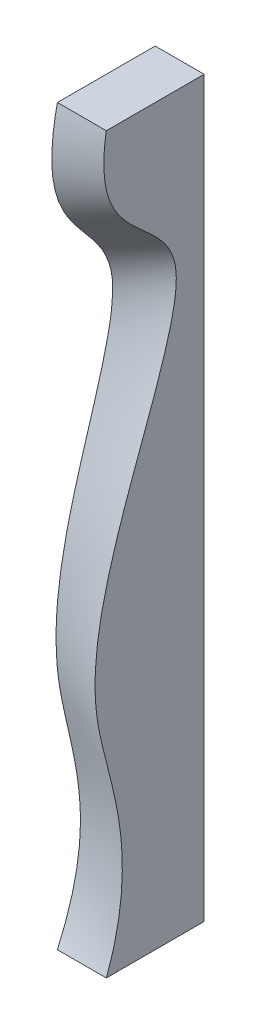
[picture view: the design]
ISO-10303-21;
HEADER;
FILE_DESCRIPTION(('STEP AP214'),'2;1');
FILE_NAME('part.step','',(''),(''),'','','');
FILE_SCHEMA(('AUTOMOTIVE_DESIGN { 1 0 10303 214 1 1 1 1 }'));
ENDSEC;
DATA;
#1=APPLICATION_CONTEXT('core data for automotive mechanical design processes');
#2=APPLICATION_PROTOCOL_DEFINITION('international standard','automotive_design',2000,#1);
#3=PRODUCT_CONTEXT('',#1,'mechanical');
#4=PRODUCT('Part','Part','',(#3));
#5=PRODUCT_RELATED_PRODUCT_CATEGORY('part','',(#4));
#6=PRODUCT_DEFINITION_FORMATION('','',#4);
#7=PRODUCT_DEFINITION_CONTEXT('part definition',#1,'design');
#8=PRODUCT_DEFINITION('design','',#6,#7);
#9=PRODUCT_DEFINITION_SHAPE('','',#8);
#10=(LENGTH_UNIT() NAMED_UNIT(*) SI_UNIT(.MILLI.,.METRE.));
#11=(NAMED_UNIT(*) PLANE_ANGLE_UNIT() SI_UNIT($,.RADIAN.));
#12=(NAMED_UNIT(*) SI_UNIT($,.STERADIAN.) SOLID_ANGLE_UNIT());
#13=UNCERTAINTY_MEASURE_WITH_UNIT(LENGTH_MEASURE(1.E-05),#10,'distance_accuracy_value','');
#14=(GEOMETRIC_REPRESENTATION_CONTEXT(3) GLOBAL_UNCERTAINTY_ASSIGNED_CONTEXT((#13)) GLOBAL_UNIT_ASSIGNED_CONTEXT((#10,
#11,#12)) REPRESENTATION_CONTEXT('',''));
#15=CARTESIAN_POINT('',(0.,0.,0.));
#16=DIRECTION('',(0.,0.,1.));
#17=DIRECTION('',(1.,0.,0.));
#18=AXIS2_PLACEMENT_3D('',#15,#16,#17);
#19=CARTESIAN_POINT('',(-350.,375.,253.120113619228));
#20=DIRECTION('',(1.,0.,0.));
#21=DIRECTION('',(0.,0.,-1.));
#22=AXIS2_PLACEMENT_3D('',#19,#20,#21);
#23=PLANE('',#22);
#24=CARTESIAN_POINT('',(-350.,375.,100.));
#25=CARTESIAN_POINT('',(-350.,373.56789695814,100.239089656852));
#26=CARTESIAN_POINT('',(-350.,372.133426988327,100.464333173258));
#27=CARTESIAN_POINT('',(-350.,369.251623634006,100.885895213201));
#28=CARTESIAN_POINT('',(-350.,367.804264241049,101.082035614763));
#29=CARTESIAN_POINT('',(-350.,364.899242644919,101.442049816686));
#30=CARTESIAN_POINT('',(-350.,363.441562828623,101.605782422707));
#31=CARTESIAN_POINT('',(-350.,360.518482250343,101.897471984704));
#32=CARTESIAN_POINT('',(-350.,359.053071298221,102.025327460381));
#33=CARTESIAN_POINT('',(-350.,356.117091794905,102.241663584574));
#34=CARTESIAN_POINT('',(-350.,354.646518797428,102.330084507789));
#35=CARTESIAN_POINT('',(-350.,351.702774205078,102.463840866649));
#36=CARTESIAN_POINT('',(-350.,350.229601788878,102.509158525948));
#37=CARTESIAN_POINT('',(-350.,347.250122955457,102.553387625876));
#38=CARTESIAN_POINT('',(-350.,345.743800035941,102.55125706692));
#39=CARTESIAN_POINT('',(-350.,342.733740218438,102.493788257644));
#40=CARTESIAN_POINT('',(-350.,341.230002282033,102.438507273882));
#41=CARTESIAN_POINT('',(-350.,338.227820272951,102.270466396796));
#42=CARTESIAN_POINT('',(-350.,336.729371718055,102.157788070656));
#43=CARTESIAN_POINT('',(-350.,333.740481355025,101.870625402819));
#44=CARTESIAN_POINT('',(-350.,332.250031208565,101.696228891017));
#45=CARTESIAN_POINT('',(-350.,329.279876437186,101.281307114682));
#46=CARTESIAN_POINT('',(-350.,327.800162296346,101.04085040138));
#47=CARTESIAN_POINT('',(-350.,324.854131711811,100.48952647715));
#48=CARTESIAN_POINT('',(-350.,323.387812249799,100.178675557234));
#49=CARTESIAN_POINT('',(-350.,320.958980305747,99.5989195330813));
#50=CARTESIAN_POINT('',(-350.,319.991518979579,99.3505932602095));
#51=CARTESIAN_POINT('',(-350.,318.065547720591,98.8200536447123));
#52=CARTESIAN_POINT('',(-350.,317.107040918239,98.5378288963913));
#53=CARTESIAN_POINT('',(-350.,315.200747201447,97.9388584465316));
#54=CARTESIAN_POINT('',(-350.,314.252961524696,97.6221088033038));
#55=CARTESIAN_POINT('',(-350.,312.369764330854,96.9537079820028));
#56=CARTESIAN_POINT('',(-350.,311.4343528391,96.6020567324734));
#57=CARTESIAN_POINT('',(-350.,309.577470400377,95.8637615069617));
#58=CARTESIAN_POINT('',(-350.,308.655999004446,95.477118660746));
#59=CARTESIAN_POINT('',(-350.,306.841363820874,94.674780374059));
#60=CARTESIAN_POINT('',(-350.,305.947983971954,94.2595735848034));
#61=CARTESIAN_POINT('',(-350.,304.177397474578,93.395896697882));
#62=CARTESIAN_POINT('',(-350.,303.300191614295,92.947424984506));
#63=CARTESIAN_POINT('',(-350.,301.56310999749,92.0181262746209));
#64=CARTESIAN_POINT('',(-350.,300.703234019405,91.5372996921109));
#65=CARTESIAN_POINT('',(-350.,299.001774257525,90.5445478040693));
#66=CARTESIAN_POINT('',(-350.,298.160188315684,90.0326261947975));
#67=CARTESIAN_POINT('',(-350.,296.496071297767,88.9792927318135));
#68=CARTESIAN_POINT('',(-350.,295.673534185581,88.4378904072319));
#69=CARTESIAN_POINT('',(-350.,294.082580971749,87.3511275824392));
#70=CARTESIAN_POINT('',(-350.,293.313360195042,86.8069433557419));
#71=CARTESIAN_POINT('',(-350.,291.792327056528,85.6946976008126));
#72=CARTESIAN_POINT('',(-350.,291.040515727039,85.1266346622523));
#73=CARTESIAN_POINT('',(-350.,289.553643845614,83.9681610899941));
#74=CARTESIAN_POINT('',(-350.,288.818593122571,83.3777378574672));
#75=CARTESIAN_POINT('',(-350.,287.365099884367,82.1767417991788));
#76=CARTESIAN_POINT('',(-350.,286.646658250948,81.5661679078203));
#77=CARTESIAN_POINT('',(-350.,285.224965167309,80.3263025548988));
#78=CARTESIAN_POINT('',(-350.,284.521728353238,79.6969943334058));
#79=CARTESIAN_POINT('',(-350.,283.130064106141,78.4221887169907));
#80=CARTESIAN_POINT('',(-350.,282.441637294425,77.7766906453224));
#81=CARTESIAN_POINT('',(-350.,280.396837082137,75.8190046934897));
#82=CARTESIAN_POINT('',(-350.,279.060828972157,74.4855238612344));
#83=CARTESIAN_POINT('',(-350.,276.411292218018,71.7573052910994));
#84=CARTESIAN_POINT('',(-350.,275.098410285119,70.361945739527));
#85=CARTESIAN_POINT('',(-350.,272.502083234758,67.5464175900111));
#86=CARTESIAN_POINT('',(-350.,271.218614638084,66.1262704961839));
#87=CARTESIAN_POINT('',(-350.,268.663277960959,63.276236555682));
#88=CARTESIAN_POINT('',(-350.,267.391407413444,61.8463518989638));
#89=CARTESIAN_POINT('',(-350.,264.840495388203,58.9926347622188));
#90=CARTESIAN_POINT('',(-350.,263.561453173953,57.5688029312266));
#91=CARTESIAN_POINT('',(-350.,261.510011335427,55.327254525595));
#92=CARTESIAN_POINT('',(-350.,260.746191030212,54.5017191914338));
#93=CARTESIAN_POINT('',(-350.,259.205543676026,52.8628311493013));
#94=CARTESIAN_POINT('',(-350.,258.428716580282,52.0494784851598));
#95=CARTESIAN_POINT('',(-350.,256.857987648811,50.4390140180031));
#96=CARTESIAN_POINT('',(-350.,256.064081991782,49.6419059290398));
#97=CARTESIAN_POINT('',(-350.,254.455574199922,48.0687110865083));
#98=CARTESIAN_POINT('',(-350.,253.64097123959,47.292625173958));
#99=CARTESIAN_POINT('',(-350.,251.993996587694,45.7724161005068));
#100=CARTESIAN_POINT('',(-350.,251.161810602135,45.0280924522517));
#101=CARTESIAN_POINT('',(-350.,249.470785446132,43.5704691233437));
#102=CARTESIAN_POINT('',(-350.,248.611949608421,42.8571655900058));
#103=CARTESIAN_POINT('',(-350.,246.865450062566,41.4672465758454));
#104=CARTESIAN_POINT('',(-350.,245.977795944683,40.790619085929));
#105=CARTESIAN_POINT('',(-350.,244.171990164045,39.4795445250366));
#106=CARTESIAN_POINT('',(-350.,243.253843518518,38.8450905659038));
#107=CARTESIAN_POINT('',(-350.,241.383239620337,37.6217034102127));
#108=CARTESIAN_POINT('',(-350.,240.430678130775,37.0329291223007));
#109=CARTESIAN_POINT('',(-350.,238.494672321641,35.9083356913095));
#110=CARTESIAN_POINT('',(-350.,237.511226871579,35.3725184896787));
#111=CARTESIAN_POINT('',(-350.,235.515305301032,34.3582211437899));
#112=CARTESIAN_POINT('',(-350.,234.502832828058,33.8797338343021));
#113=CARTESIAN_POINT('',(-350.,232.451607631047,32.9832570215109));
#114=CARTESIAN_POINT('',(-350.,231.412858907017,32.5652583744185));
#115=CARTESIAN_POINT('',(-350.,229.312312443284,31.7914562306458));
#116=CARTESIAN_POINT('',(-350.,228.250511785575,31.435660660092));
#117=CARTESIAN_POINT('',(-350.,226.107907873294,30.786745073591));
#118=CARTESIAN_POINT('',(-350.,225.027104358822,30.4936259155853));
#119=CARTESIAN_POINT('',(-350.,223.12719120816,30.0357911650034));
#120=CARTESIAN_POINT('',(-350.,222.311345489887,29.8573723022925));
#121=CARTESIAN_POINT('',(-350.,220.673044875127,29.5340995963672));
#122=CARTESIAN_POINT('',(-350.,219.850590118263,29.3892450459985));
#123=CARTESIAN_POINT('',(-350.,218.200638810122,29.1320416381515));
#124=CARTESIAN_POINT('',(-350.,217.37314227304,29.0196926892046));
#125=CARTESIAN_POINT('',(-350.,215.714679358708,28.8262320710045));
#126=CARTESIAN_POINT('',(-350.,214.883713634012,28.745114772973));
#127=CARTESIAN_POINT('',(-350.,213.217270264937,28.612484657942));
#128=CARTESIAN_POINT('',(-350.,212.381786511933,28.5610486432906));
#129=CARTESIAN_POINT('',(-350.,211.127690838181,28.5051938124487));
#130=CARTESIAN_POINT('',(-350.,210.70952206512,28.4901254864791));
#131=CARTESIAN_POINT('',(-350.,209.872988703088,28.4668851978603));
#132=CARTESIAN_POINT('',(-350.,209.454624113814,28.4587132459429));
#133=CARTESIAN_POINT('',(-350.,208.617811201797,28.4489030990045));
#134=CARTESIAN_POINT('',(-350.,208.199362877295,28.4472650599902));
#135=CARTESIAN_POINT('',(-350.,207.362492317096,28.4501877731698));
#136=CARTESIAN_POINT('',(-350.,206.944070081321,28.4547485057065));
#137=CARTESIAN_POINT('',(-350.,205.689091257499,28.4772474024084));
#138=CARTESIAN_POINT('',(-350.,204.852684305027,28.5040008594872));
#139=CARTESIAN_POINT('',(-350.,202.858447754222,28.5930951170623));
#140=CARTESIAN_POINT('',(-350.,201.701057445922,28.6651812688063));
#141=CARTESIAN_POINT('',(-350.,199.388964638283,28.8447465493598));
#142=CARTESIAN_POINT('',(-350.,198.234262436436,28.9522294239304));
#143=CARTESIAN_POINT('',(-350.,195.927477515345,29.1982297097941));
#144=CARTESIAN_POINT('',(-350.,194.775396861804,29.3367663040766));
#145=CARTESIAN_POINT('',(-350.,192.474903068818,29.6410702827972));
#146=CARTESIAN_POINT('',(-350.,191.326489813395,29.8068367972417));
#147=CARTESIAN_POINT('',(-350.,189.031130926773,30.1627618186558));
#148=CARTESIAN_POINT('',(-350.,187.884192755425,30.3529681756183));
#149=CARTESIAN_POINT('',(-350.,185.594075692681,30.75476513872));
#150=CARTESIAN_POINT('',(-350.,184.450896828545,30.9663558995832));
#151=CARTESIAN_POINT('',(-350.,182.166113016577,31.4089671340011));
#152=CARTESIAN_POINT('',(-350.,181.024514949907,31.6400230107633));
#153=CARTESIAN_POINT('',(-350.,178.744907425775,32.1191484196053));
#154=CARTESIAN_POINT('',(-350.,177.606897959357,32.3672179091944));
#155=CARTESIAN_POINT('',(-350.,175.333202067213,32.8788776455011));
#156=CARTESIAN_POINT('',(-350.,174.197519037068,33.1424829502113));
#157=CARTESIAN_POINT('',(-350.,171.929448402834,33.6835429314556));
#158=CARTESIAN_POINT('',(-350.,170.797060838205,33.9609977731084));
#159=CARTESIAN_POINT('',(-350.,168.535768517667,34.5283694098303));
#160=CARTESIAN_POINT('',(-350.,167.406862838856,34.8182825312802));
#161=CARTESIAN_POINT('',(-350.,165.15203596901,35.4095044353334));
#162=CARTESIAN_POINT('',(-350.,164.026114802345,35.7108133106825));
#163=CARTESIAN_POINT('',(-350.,160.622829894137,36.6383721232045));
#164=CARTESIAN_POINT('',(-350.,158.349838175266,37.2806988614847));
#165=CARTESIAN_POINT('',(-350.,153.817929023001,38.5994454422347));
#166=CARTESIAN_POINT('',(-350.,151.558994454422,39.275806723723));
#167=CARTESIAN_POINT('',(-350.,147.052777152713,40.6569234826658));
#168=CARTESIAN_POINT('',(-350.,144.805483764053,41.3616442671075));
#169=CARTESIAN_POINT('',(-350.,140.320483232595,42.794777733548));
#170=CARTESIAN_POINT('',(-350.,138.082769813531,43.5231708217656));
#171=CARTESIAN_POINT('',(-350.,133.615104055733,44.9997233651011));
#172=CARTESIAN_POINT('',(-350.,131.385148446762,45.7478729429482));
#173=CARTESIAN_POINT('',(-350.,126.931365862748,47.2606037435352));
#174=CARTESIAN_POINT('',(-350.,124.707537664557,48.0251813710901));
#175=CARTESIAN_POINT('',(-350.,119.785684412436,49.7341411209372));
#176=CARTESIAN_POINT('',(-350.,117.088781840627,50.6817525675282));
#177=CARTESIAN_POINT('',(-350.,111.700355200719,52.5921591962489));
#178=CARTESIAN_POINT('',(-350.,109.008831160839,53.5549544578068));
#179=CARTESIAN_POINT('',(-350.,103.628833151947,55.4918556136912));
#180=CARTESIAN_POINT('',(-350.,100.940360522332,56.4659652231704));
#181=CARTESIAN_POINT('',(-350.,95.5660534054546,58.4214102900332));
#182=CARTESIAN_POINT('',(-350.,92.8802189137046,59.4027457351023));
#183=CARTESIAN_POINT('',(-350.,87.5085077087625,61.3697351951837));
#184=CARTESIAN_POINT('',(-350.,84.8226317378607,62.3553912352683));
#185=CARTESIAN_POINT('',(-350.,79.4511021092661,64.327308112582));
#186=CARTESIAN_POINT('',(-350.,76.7654484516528,65.3135689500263));
#187=CARTESIAN_POINT('',(-350.,68.7034808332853,68.2700339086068));
#188=CARTESIAN_POINT('',(-350.,63.3258149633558,70.2365726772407));
#189=CARTESIAN_POINT('',(-350.,52.5539221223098,74.1383743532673));
#190=CARTESIAN_POINT('',(-350.,47.1596849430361,76.07360917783));
#191=CARTESIAN_POINT('',(-350.,36.3453884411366,79.8902508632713));
#192=CARTESIAN_POINT('',(-350.,30.925307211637,81.771596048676));
#193=CARTESIAN_POINT('',(-350.,22.8083364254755,84.5219137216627));
#194=CARTESIAN_POINT('',(-350.,20.1217496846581,85.4212926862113));
#195=CARTESIAN_POINT('',(-350.,14.7410514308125,87.1972909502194));
#196=CARTESIAN_POINT('',(-350.,12.0469399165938,88.0739102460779));
#197=CARTESIAN_POINT('',(-350.,6.6498316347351,89.8012548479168));
#198=CARTESIAN_POINT('',(-350.,3.94683321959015,90.651975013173));
#199=CARTESIAN_POINT('',(-350.,-1.46831763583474,92.3238101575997));
#200=CARTESIAN_POINT('',(-350.,-4.18047007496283,93.1449251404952));
#201=CARTESIAN_POINT('',(-350.,-9.61262167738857,94.7531589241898));
#202=CARTESIAN_POINT('',(-350.,-12.332613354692,95.5403029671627));
#203=CARTESIAN_POINT('',(-350.,-17.7831651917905,97.0771916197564));
#204=CARTESIAN_POINT('',(-350.,-20.5137253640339,97.826936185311));
#205=CARTESIAN_POINT('',(-350.,-25.982410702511,99.2836855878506));
#206=CARTESIAN_POINT('',(-350.,-28.7205212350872,99.9907452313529));
#207=CARTESIAN_POINT('',(-350.,-34.2083123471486,101.358474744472));
#208=CARTESIAN_POINT('',(-350.,-36.9579928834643,102.019144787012));
#209=CARTESIAN_POINT('',(-350.,-42.465705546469,103.288209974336));
#210=CARTESIAN_POINT('',(-350.,-45.2237222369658,103.896671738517));
#211=CARTESIAN_POINT('',(-350.,-50.7516232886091,105.056834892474));
#212=CARTESIAN_POINT('',(-350.,-53.5215078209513,105.608535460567));
#213=CARTESIAN_POINT('',(-350.,-61.8466405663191,107.169487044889));
#214=CARTESIAN_POINT('',(-350.,-67.4201789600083,108.085247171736));
#215=CARTESIAN_POINT('',(-350.,-75.1359915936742,109.142180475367));
#216=CARTESIAN_POINT('',(-350.,-77.261213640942,109.411375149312));
#217=CARTESIAN_POINT('',(-350.,-81.5174880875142,109.904006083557));
#218=CARTESIAN_POINT('',(-350.,-83.6485416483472,110.127432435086));
#219=CARTESIAN_POINT('',(-350.,-87.9154096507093,110.525715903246));
#220=CARTESIAN_POINT('',(-350.,-90.0512245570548,110.700568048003));
#221=CARTESIAN_POINT('',(-350.,-94.3266132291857,110.998995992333));
#222=CARTESIAN_POINT('',(-350.,-96.4661872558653,111.122568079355));
#223=CARTESIAN_POINT('',(-350.,-100.746400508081,111.315784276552));
#224=CARTESIAN_POINT('',(-350.,-102.887038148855,111.385463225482));
#225=CARTESIAN_POINT('',(-350.,-107.169397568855,111.468630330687));
#226=CARTESIAN_POINT('',(-350.,-109.311119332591,111.482119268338));
#227=CARTESIAN_POINT('',(-350.,-113.593892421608,111.450734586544));
#228=CARTESIAN_POINT('',(-350.,-115.734943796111,111.405867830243));
#229=CARTESIAN_POINT('',(-350.,-120.014680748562,111.255861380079));
#230=CARTESIAN_POINT('',(-350.,-122.153366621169,111.150730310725));
#231=CARTESIAN_POINT('',(-350.,-125.354872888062,110.946814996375));
#232=CARTESIAN_POINT('',(-350.,-126.419219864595,110.871301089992));
#233=CARTESIAN_POINT('',(-350.,-128.54664947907,110.704714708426));
#234=CARTESIAN_POINT('',(-350.,-129.609732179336,110.613643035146));
#235=CARTESIAN_POINT('',(-350.,-131.734397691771,110.415769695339));
#236=CARTESIAN_POINT('',(-350.,-132.79598054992,110.308968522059));
#237=CARTESIAN_POINT('',(-350.,-134.917425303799,110.079473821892));
#238=CARTESIAN_POINT('',(-350.,-135.97728720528,109.956780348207));
#239=CARTESIAN_POINT('',(-350.,-138.095311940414,109.695316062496));
#240=CARTESIAN_POINT('',(-350.,-139.153474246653,109.556540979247));
#241=CARTESIAN_POINT('',(-350.,-141.267559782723,109.262787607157));
#242=CARTESIAN_POINT('',(-350.,-142.323482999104,109.107809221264));
#243=CARTESIAN_POINT('',(-350.,-143.905427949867,108.863104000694));
#244=CARTESIAN_POINT('',(-350.,-144.43240328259,108.77949877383));
#245=CARTESIAN_POINT('',(-350.,-145.485684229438,108.608166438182));
#246=CARTESIAN_POINT('',(-350.,-146.011989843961,108.520439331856));
#247=CARTESIAN_POINT('',(-350.,-147.063839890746,108.34102058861));
#248=CARTESIAN_POINT('',(-350.,-147.589384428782,108.249329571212));
#249=CARTESIAN_POINT('',(-350.,-148.639807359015,108.062210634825));
#250=CARTESIAN_POINT('',(-350.,-149.16468575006,107.966782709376));
#251=CARTESIAN_POINT('',(-350.,-151.085335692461,107.610940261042));
#252=CARTESIAN_POINT('',(-350.,-152.479135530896,107.339835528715));
#253=CARTESIAN_POINT('',(-350.,-155.262615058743,106.777184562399));
#254=CARTESIAN_POINT('',(-350.,-156.652294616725,106.485637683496));
#255=CARTESIAN_POINT('',(-350.,-158.734294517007,106.036503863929));
#256=CARTESIAN_POINT('',(-350.,-159.427896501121,105.884818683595));
#257=CARTESIAN_POINT('',(-350.,-160.814312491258,105.577887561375));
#258=CARTESIAN_POINT('',(-350.,-161.507126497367,105.422641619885));
#259=CARTESIAN_POINT('',(-350.,-163.584440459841,104.952017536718));
#260=CARTESIAN_POINT('',(-350.,-164.967833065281,104.631748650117));
#261=CARTESIAN_POINT('',(-350.,-169.1156139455,103.654780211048));
#262=CARTESIAN_POINT('',(-350.,-171.876254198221,102.982215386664));
#263=CARTESIAN_POINT('',(-350.,-177.393027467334,101.612858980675));
#264=CARTESIAN_POINT('',(-350.,-180.149157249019,100.916054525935));
#265=CARTESIAN_POINT('',(-350.,-185.660752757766,99.5150069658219));
#266=CARTESIAN_POINT('',(-350.,-188.416217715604,98.810760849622));
#267=CARTESIAN_POINT('',(-350.,-193.929920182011,97.4101071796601));
#268=CARTESIAN_POINT('',(-350.,-196.688158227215,96.7137017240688));
#269=CARTESIAN_POINT('',(-350.,-202.20819860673,95.3430815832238));
#270=CARTESIAN_POINT('',(-350.,-204.969997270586,94.6688522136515));
#271=CARTESIAN_POINT('',(-350.,-210.50132605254,93.3545067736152));
#272=CARTESIAN_POINT('',(-350.,-213.270854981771,92.714385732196));
#273=CARTESIAN_POINT('',(-350.,-218.818970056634,91.4794186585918));
#274=CARTESIAN_POINT('',(-350.,-221.59755249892,90.8845560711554));
#275=CARTESIAN_POINT('',(-350.,-227.164867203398,89.7498767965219));
#276=CARTESIAN_POINT('',(-350.,-229.953594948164,89.2100381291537));
#277=CARTESIAN_POINT('',(-350.,-234.144971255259,88.4478482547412));
#278=CARTESIAN_POINT('',(-350.,-235.54332204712,88.2017376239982));
#279=CARTESIAN_POINT('',(-350.,-238.342864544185,87.726287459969));
#280=CARTESIAN_POINT('',(-350.,-239.744056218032,87.4969477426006));
#281=CARTESIAN_POINT('',(-350.,-242.549328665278,87.0559114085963));
#282=CARTESIAN_POINT('',(-350.,-243.953409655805,86.8442161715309));
#283=CARTESIAN_POINT('',(-350.,-246.764291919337,86.4392925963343));
#284=CARTESIAN_POINT('',(-350.,-248.171093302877,86.2460650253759));
#285=CARTESIAN_POINT('',(-350.,-251.386360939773,85.8267815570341));
#286=CARTESIAN_POINT('',(-350.,-253.195643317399,85.6069466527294));
#287=CARTESIAN_POINT('',(-350.,-256.817956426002,85.2003497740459));
#288=CARTESIAN_POINT('',(-350.,-258.630987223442,85.013588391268));
#289=CARTESIAN_POINT('',(-350.,-262.260360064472,84.6743642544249));
#290=CARTESIAN_POINT('',(-350.,-264.076702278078,84.5219033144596));
#291=CARTESIAN_POINT('',(-350.,-267.712045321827,84.252359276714));
#292=CARTESIAN_POINT('',(-350.,-269.531046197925,84.1352767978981));
#293=CARTESIAN_POINT('',(-350.,-273.17166035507,83.937381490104));
#294=CARTESIAN_POINT('',(-350.,-274.993274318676,83.8565811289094));
#295=CARTESIAN_POINT('',(-350.,-278.637778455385,83.7320908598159));
#296=CARTESIAN_POINT('',(-350.,-280.46066865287,83.6884016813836));
#297=CARTESIAN_POINT('',(-350.,-285.929985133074,83.6140467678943));
#298=CARTESIAN_POINT('',(-350.,-289.577368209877,83.6400765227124));
#299=CARTESIAN_POINT('',(-350.,-296.872971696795,83.8477084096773));
#300=CARTESIAN_POINT('',(-350.,-300.521185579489,84.0295372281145));
#301=CARTESIAN_POINT('',(-350.,-307.806432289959,84.5519024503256));
#302=CARTESIAN_POINT('',(-350.,-311.443464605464,84.8924460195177));
#303=CARTESIAN_POINT('',(-350.,-318.697673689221,85.7337734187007));
#304=CARTESIAN_POINT('',(-350.,-322.314857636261,86.2344948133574));
#305=CARTESIAN_POINT('',(-350.,-327.720694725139,87.1059032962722));
#306=CARTESIAN_POINT('',(-350.,-329.519242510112,87.4164116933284));
#307=CARTESIAN_POINT('',(-350.,-333.108956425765,88.0774365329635));
#308=CARTESIAN_POINT('',(-350.,-334.900122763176,88.427951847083));
#309=CARTESIAN_POINT('',(-350.,-338.320003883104,89.1368349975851));
#310=CARTESIAN_POINT('',(-350.,-339.949401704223,89.491916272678));
#311=CARTESIAN_POINT('',(-350.,-343.200371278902,90.2350216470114));
#312=CARTESIAN_POINT('',(-350.,-344.821944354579,90.6230399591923));
#313=CARTESIAN_POINT('',(-350.,-348.056747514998,91.4317202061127));
#314=CARTESIAN_POINT('',(-350.,-349.669978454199,91.8523787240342));
#315=CARTESIAN_POINT('',(-350.,-352.887606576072,92.7259670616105));
#316=CARTESIAN_POINT('',(-350.,-354.492004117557,93.1788955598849));
#317=CARTESIAN_POINT('',(-350.,-357.687112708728,94.1152922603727));
#318=CARTESIAN_POINT('',(-350.,-359.277849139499,94.5986738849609));
#319=CARTESIAN_POINT('',(-350.,-362.44961487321,95.59656347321));
#320=CARTESIAN_POINT('',(-350.,-364.030643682,96.1110730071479));
#321=CARTESIAN_POINT('',(-350.,-367.182572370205,97.1706277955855));
#322=CARTESIAN_POINT('',(-350.,-368.75347142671,97.7156754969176));
#323=CARTESIAN_POINT('',(-350.,-371.884757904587,98.8356276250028));
#324=CARTESIAN_POINT('',(-350.,-373.445144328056,99.4105348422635));
#325=CARTESIAN_POINT('',(-350.,-375.,100.));
#326=B_SPLINE_CURVE_WITH_KNOTS('',3,(#24,#25,#26,#27,#28,#29,#30,#31,#32,#33,#34,#35,#36,#37,
#38,#39,#40,#41,#42,#43,#44,#45,#46,#47,#48,#49,#50,#51,#52,#53,#54,#55,#56,#57,#58,#59,#60,#61,
#62,#63,#64,#65,#66,#67,#68,#69,#70,#71,#72,#73,#74,#75,#76,#77,#78,#79,#80,#81,#82,#83,#84,#85,
#86,#87,#88,#89,#90,#91,#92,#93,#94,#95,#96,#97,#98,#99,#100,#101,#102,#103,#104,#105,#106,#107,
#108,#109,#110,#111,#112,#113,#114,#115,#116,#117,#118,#119,#120,#121,#122,#123,#124,#125,#126,
#127,#128,#129,#130,#131,#132,#133,#134,#135,#136,#137,#138,#139,#140,#141,#142,#143,#144,#145,
#146,#147,#148,#149,#150,#151,#152,#153,#154,#155,#156,#157,#158,#159,#160,#161,#162,#163,#164,
#165,#166,#167,#168,#169,#170,#171,#172,#173,#174,#175,#176,#177,#178,#179,#180,#181,#182,#183,
#184,#185,#186,#187,#188,#189,#190,#191,#192,#193,#194,#195,#196,#197,#198,#199,#200,#201,#202,
#203,#204,#205,#206,#207,#208,#209,#210,#211,#212,#213,#214,#215,#216,#217,#218,#219,#220,#221,
#222,#223,#224,#225,#226,#227,#228,#229,#230,#231,#232,#233,#234,#235,#236,#237,#238,#239,#240,
#241,#242,#243,#244,#245,#246,#247,#248,#249,#250,#251,#252,#253,#254,#255,#256,#257,#258,#259,
#260,#261,#262,#263,#264,#265,#266,#267,#268,#269,#270,#271,#272,#273,#274,#275,#276,#277,#278,
#279,#280,#281,#282,#283,#284,#285,#286,#287,#288,#289,#290,#291,#292,#293,#294,#295,#296,#297,
#298,#299,#300,#301,#302,#303,#304,#305,#306,#307,#308,#309,#310,#311,#312,#313,#314,#315,#316,
#317,#318,#319,#320,#321,#322,#323,#324,#325),.UNSPECIFIED.,.F.,.F.,(4,2,2,2,2,2,2,2,2,2,2,2,2,
2,2,2,2,2,2,2,2,2,2,2,2,2,2,2,2,2,2,2,2,2,2,2,2,2,2,2,2,2,2,2,2,2,2,2,2,2,2,2,2,2,2,2,2,2,2,2,2,
2,2,2,2,2,2,2,2,2,2,2,2,2,2,2,2,2,2,2,2,2,2,2,2,2,2,2,2,2,2,2,2,2,2,2,2,2,2,2,2,2,2,2,2,2,2,2,2,
2,2,2,2,2,2,2,2,2,2,2,2,2,2,2,2,2,2,2,2,2,2,2,2,2,2,2,2,2,2,2,2,2,2,2,2,2,2,2,2,2,4),(0.,
4.35578491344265,8.73721706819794,13.1373372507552,17.5497807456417,21.9688845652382,
26.3898100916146,30.9079164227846,35.4211602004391,39.9280080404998,44.4284678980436,
48.9242751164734,53.4190429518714,56.4149627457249,59.4118934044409,62.409166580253,
65.4064458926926,68.4036284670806,71.3583902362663,74.3132956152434,77.2681631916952,
80.2226802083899,83.1762478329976,86.002518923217,88.828957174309,91.6570123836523,
94.4852173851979,97.3160334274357,100.146967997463,105.808378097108,111.555513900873,
117.297889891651,123.039014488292,128.780739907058,132.154711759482,135.52869574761,
138.903442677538,142.278324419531,145.627154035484,148.975566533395,152.322875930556,
155.66963726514,159.027562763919,162.38561132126,165.743239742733,169.10036007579,
172.457907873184,175.815501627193,178.320207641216,180.824860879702,183.329507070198,
185.833701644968,188.344347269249,189.599621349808,190.854897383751,192.110203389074,
193.365505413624,195.875694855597,199.353943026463,202.832559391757,206.313330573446,
209.793990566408,213.281572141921,216.769178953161,220.263271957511,223.757356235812,
227.254884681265,230.752454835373,234.249000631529,237.745574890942,244.831208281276,
251.905041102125,258.970468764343,266.030190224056,273.086446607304,280.141174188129,
288.716730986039,297.29233265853,305.870834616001,314.449321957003,323.032387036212,
331.615455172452,348.793277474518,365.985739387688,383.197149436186,391.69645954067,
400.195770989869,408.696758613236,417.19774516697,425.692302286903,434.18686941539,
442.670286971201,451.15367290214,459.626067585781,468.098584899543,485.034963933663,
491.461219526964,497.888864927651,504.317167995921,510.745936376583,517.170545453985,
523.595065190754,530.018829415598,536.441674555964,539.64264824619,542.843456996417,
546.044165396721,549.244863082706,552.446412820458,555.647981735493,557.24866675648,
558.849350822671,560.449785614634,562.050223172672,566.309770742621,570.569452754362,
572.699428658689,574.829404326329,579.089292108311,587.613216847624,596.141739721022,
604.673856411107,613.208204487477,621.736782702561,630.264114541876,638.788311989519,
647.309090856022,651.56853632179,655.827935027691,660.087666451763,664.34757475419,
669.815038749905,675.282600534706,680.75045142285,686.218397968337,691.6882220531,
697.158153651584,708.097083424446,719.051956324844,730.007323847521,740.958426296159,
746.433519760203,751.908458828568,756.911042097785,761.912748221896,766.913931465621,
771.91491004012,776.902261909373,781.889865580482,786.877869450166,791.866340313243),.UNSPECIFIED.);
#327=CARTESIAN_POINT('',(-350.,375.,100.));
#328=VERTEX_POINT('',#327);
#329=CARTESIAN_POINT('',(-350.,-375.,100.));
#330=VERTEX_POINT('',#329);
#331=EDGE_CURVE('E88',#328,#330,#326,.T.);
#332=ORIENTED_EDGE('',*,*,#331,.T.);
#333=DIRECTION('',(0.,0.,-1.));
#334=VECTOR('',#333,1.);
#335=CARTESIAN_POINT('',(-350.,-375.,253.120113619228));
#336=LINE('',#335,#334);
#337=CARTESIAN_POINT('',(-350.,-375.,0.));
#338=VERTEX_POINT('',#337);
#339=EDGE_CURVE('E50',#330,#338,#336,.T.);
#340=ORIENTED_EDGE('',*,*,#339,.T.);
#341=DIRECTION('',(0.,-1.,0.));
#342=VECTOR('',#341,1.);
#343=CARTESIAN_POINT('',(-350.,375.,0.));
#344=LINE('',#343,#342);
#345=CARTESIAN_POINT('',(-350.,375.,0.));
#346=VERTEX_POINT('',#345);
#347=EDGE_CURVE('E87',#346,#338,#344,.T.);
#348=ORIENTED_EDGE('',*,*,#347,.F.);
#349=DIRECTION('',(0.,0.,-1.));
#350=VECTOR('',#349,1.);
#351=CARTESIAN_POINT('',(-350.,375.,253.120113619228));
#352=LINE('',#351,#350);
#353=EDGE_CURVE('E65',#328,#346,#352,.T.);
#354=ORIENTED_EDGE('',*,*,#353,.F.);
#355=EDGE_LOOP('',(#332,#340,#348,#354));
#356=FACE_BOUND('',#355,.T.);
#357=ADVANCED_FACE('F35',(#356),#23,.T.);
#358=CARTESIAN_POINT('',(0.,0.,0.));
#359=DIRECTION('',(0.,0.,-1.));
#360=DIRECTION('',(-1.,0.,0.));
#361=AXIS2_PLACEMENT_3D('',#358,#359,#360);
#362=PLANE('',#361);
#363=DIRECTION('',(1.,0.,0.));
#364=VECTOR('',#363,1.);
#365=CARTESIAN_POINT('',(-750.,-375.,0.));
#366=LINE('',#365,#364);
#367=CARTESIAN_POINT('',(-400.,-375.,0.));
#368=VERTEX_POINT('',#367);
#369=EDGE_CURVE('E79',#368,#338,#366,.T.);
#370=ORIENTED_EDGE('',*,*,#369,.F.);
#371=DIRECTION('',(0.,1.,0.));
#372=VECTOR('',#371,1.);
#373=CARTESIAN_POINT('',(-400.,375.,0.));
#374=LINE('',#373,#372);
#375=CARTESIAN_POINT('',(-400.,375.,0.));
#376=VERTEX_POINT('',#375);
#377=EDGE_CURVE('E157',#368,#376,#374,.T.);
#378=ORIENTED_EDGE('',*,*,#377,.T.);
#379=DIRECTION('',(-1.,0.,0.));
#380=VECTOR('',#379,1.);
#381=CARTESIAN_POINT('',(-750.,375.,0.));
#382=LINE('',#381,#380);
#383=EDGE_CURVE('E93',#346,#376,#382,.T.);
#384=ORIENTED_EDGE('',*,*,#383,.F.);
#385=ORIENTED_EDGE('',*,*,#347,.T.);
#386=EDGE_LOOP('',(#370,#378,#384,#385));
#387=FACE_BOUND('',#386,.T.);
#388=ADVANCED_FACE('F91',(#387),#362,.T.);
#389=CARTESIAN_POINT('',(750.,-375.,100.));
#390=CARTESIAN_POINT('',(750.,-302.078506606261,100.));
#391=CARTESIAN_POINT('',(750.,-224.483786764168,100.));
#392=CARTESIAN_POINT('',(750.,-61.5160152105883,100.));
#393=CARTESIAN_POINT('',(750.,39.4445673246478,100.));
#394=CARTESIAN_POINT('',(750.,211.849847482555,100.));
#395=CARTESIAN_POINT('',(750.,298.882075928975,100.));
#396=CARTESIAN_POINT('',(750.,375.,100.));
#397=CARTESIAN_POINT('',(669.085175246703,-375.,100.));
#398=CARTESIAN_POINT('',(669.085175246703,-302.078506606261,100.));
#399=CARTESIAN_POINT('',(669.085175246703,-234.282472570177,121.198481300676));
#400=CARTESIAN_POINT('',(669.085175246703,-62.2283080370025,120.288550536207));
#401=CARTESIAN_POINT('',(669.085175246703,68.0647781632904,82.7868169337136));
#402=CARTESIAN_POINT('',(669.085175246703,240.312514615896,73.0426687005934));
#403=CARTESIAN_POINT('',(669.085175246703,298.882075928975,100.));
#404=CARTESIAN_POINT('',(669.085175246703,375.,100.));
#405=CARTESIAN_POINT('',(500.445116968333,-375.,100.));
#406=CARTESIAN_POINT('',(517.991528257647,-284.627602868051,95.5040591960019));
#407=CARTESIAN_POINT('',(530.038001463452,-221.673003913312,150.719602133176));
#408=CARTESIAN_POINT('',(473.74510655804,-71.7416270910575,167.060530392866));
#409=CARTESIAN_POINT('',(387.213321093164,45.6135081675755,91.591323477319));
#410=CARTESIAN_POINT('',(378.694107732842,207.638743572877,66.6461848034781));
#411=CARTESIAN_POINT('',(433.17831170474,253.396603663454,122.492891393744));
#412=CARTESIAN_POINT('',(500.445116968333,375.,100.));
#413=CARTESIAN_POINT('',(285.091607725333,-375.,100.));
#414=CARTESIAN_POINT('',(309.270321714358,-264.297524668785,86.4064578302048));
#415=CARTESIAN_POINT('',(325.856840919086,-200.08226970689,164.07204721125));
#416=CARTESIAN_POINT('',(247.47112957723,-80.9425320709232,234.992870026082));
#417=CARTESIAN_POINT('',(127.240382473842,2.40271344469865,186.756001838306));
#418=CARTESIAN_POINT('',(115.567806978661,152.518027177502,151.057444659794));
#419=CARTESIAN_POINT('',(191.428893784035,202.025100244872,189.039851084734));
#420=CARTESIAN_POINT('',(285.091607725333,375.,100.));
#421=CARTESIAN_POINT('',(47.4554331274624,-375.,100.));
#422=CARTESIAN_POINT('',(51.0669239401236,-278.639867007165,99.5141662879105));
#423=CARTESIAN_POINT('',(52.9210710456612,-231.452124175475,201.325948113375));
#424=CARTESIAN_POINT('',(3.18149891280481,-90.8615864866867,272.445475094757));
#425=CARTESIAN_POINT('',(-61.0346058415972,45.7948958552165,186.157760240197));
#426=CARTESIAN_POINT('',(-59.6612105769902,205.286893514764,133.941969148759));
#427=CARTESIAN_POINT('',(-11.8049718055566,220.40073671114,189.8209162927));
#428=CARTESIAN_POINT('',(47.4554331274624,375.,100.));
#429=CARTESIAN_POINT('',(-175.903454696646,-375.,100.));
#430=CARTESIAN_POINT('',(-199.823715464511,-320.588060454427,126.731848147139));
#431=CARTESIAN_POINT('',(-216.967937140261,-300.821135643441,242.921959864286));
#432=CARTESIAN_POINT('',(-184.265304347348,-55.1410097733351,206.147478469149));
#433=CARTESIAN_POINT('',(-119.865061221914,249.096629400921,-32.5779079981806));
#434=CARTESIAN_POINT('',(-104.641938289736,431.262460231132,-94.4845569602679));
#435=CARTESIAN_POINT('',(-136.623034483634,348.137040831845,60.785640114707));
#436=CARTESIAN_POINT('',(-175.903454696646,375.,100.));
#437=CARTESIAN_POINT('',(-355.235514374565,-375.,100.));
#438=CARTESIAN_POINT('',(-319.200833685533,-282.590755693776,58.2859511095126));
#439=CARTESIAN_POINT('',(-293.075279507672,-226.888141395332,104.97090627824));
#440=CARTESIAN_POINT('',(-324.119079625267,-68.6572837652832,122.102733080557));
#441=CARTESIAN_POINT('',(-398.972481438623,73.039345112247,53.3701087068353));
#442=CARTESIAN_POINT('',(-423.398679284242,233.384819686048,47.4380317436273));
#443=CARTESIAN_POINT('',(-392.720188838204,253.575952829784,124.952096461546));
#444=CARTESIAN_POINT('',(-355.235514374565,375.,100.));
#445=CARTESIAN_POINT('',(-536.684515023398,-375.,100.));
#446=CARTESIAN_POINT('',(-494.827225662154,-277.129657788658,52.0422385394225));
#447=CARTESIAN_POINT('',(-464.573647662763,-205.017596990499,67.039018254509));
#448=CARTESIAN_POINT('',(-506.334367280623,-72.2467511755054,96.5036749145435));
#449=CARTESIAN_POINT('',(-600.216684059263,9.35641022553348,95.9941925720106));
#450=CARTESIAN_POINT('',(-628.122542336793,166.946160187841,106.349064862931));
#451=CARTESIAN_POINT('',(-587.011939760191,237.095914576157,138.331902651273));
#452=CARTESIAN_POINT('',(-536.684515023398,375.,100.));
#453=CARTESIAN_POINT('',(-644.685568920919,-375.,100.));
#454=CARTESIAN_POINT('',(-644.685568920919,-302.078506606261,100.));
#455=CARTESIAN_POINT('',(-644.685568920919,-237.237234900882,127.59081546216));
#456=CARTESIAN_POINT('',(-644.685568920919,-62.4430976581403,126.406497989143));
#457=CARTESIAN_POINT('',(-644.685568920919,76.6951111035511,77.5962366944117));
#458=CARTESIAN_POINT('',(-644.685568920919,248.895340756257,64.9137717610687));
#459=CARTESIAN_POINT('',(-644.685568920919,298.882075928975,100.));
#460=CARTESIAN_POINT('',(-644.685568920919,375.,100.));
#461=CARTESIAN_POINT('',(-750.,-375.,100.));
#462=CARTESIAN_POINT('',(-750.,-302.078506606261,100.));
#463=CARTESIAN_POINT('',(-750.,-224.483786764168,100.));
#464=CARTESIAN_POINT('',(-750.,-61.5160152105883,100.));
#465=CARTESIAN_POINT('',(-750.,39.4445673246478,100.));
#466=CARTESIAN_POINT('',(-750.,211.849847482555,100.));
#467=CARTESIAN_POINT('',(-750.,298.882075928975,100.));
#468=CARTESIAN_POINT('',(-750.,375.,100.));
#469=B_SPLINE_SURFACE_WITH_KNOTS('',3,3,((#389,#390,#391,#392,#393,#394,#395,#396),(#397,#398,
#399,#400,#401,#402,#403,#404),(#405,#406,#407,#408,#409,#410,#411,#412),(#413,#414,#415,#416,
#417,#418,#419,#420),(#421,#422,#423,#424,#425,#426,#427,#428),(#429,#430,#431,#432,#433,#434,
#435,#436),(#437,#438,#439,#440,#441,#442,#443,#444),(#445,#446,#447,#448,#449,#450,#451,#452),
(#453,#454,#455,#456,#457,#458,#459,#460),(#461,#462,#463,#464,#465,#466,#467,#468)),
.UNSPECIFIED.,.F.,.F.,.F.,(4,1,1,1,1,1,1,4),(4,1,1,1,1,4),(0.,0.161829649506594,
0.33728011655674,0.430707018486,0.637101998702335,0.783997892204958,0.789371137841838,1.),(0.,
0.291685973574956,0.310378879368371,0.65187108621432,0.695528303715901,1.),.UNSPECIFIED.);
#470=CARTESIAN_POINT('',(-400.,-375.,100.));
#471=CARTESIAN_POINT('',(-400.,-372.922978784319,99.064075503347));
#472=CARTESIAN_POINT('',(-400.,-370.836009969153,98.1501121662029));
#473=CARTESIAN_POINT('',(-400.,-366.639612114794,96.3671463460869));
#474=CARTESIAN_POINT('',(-400.,-364.530156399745,95.4982066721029));
#475=CARTESIAN_POINT('',(-400.,-360.289901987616,93.8080999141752));
#476=CARTESIAN_POINT('',(-400.,-358.159085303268,92.9869779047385));
#477=CARTESIAN_POINT('',(-400.,-353.877273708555,91.3952907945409));
#478=CARTESIAN_POINT('',(-400.,-351.726268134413,90.6247543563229));
#479=CARTESIAN_POINT('',(-400.,-347.405258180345,89.136961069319));
#480=CARTESIAN_POINT('',(-400.,-345.235248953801,88.4197182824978));
#481=CARTESIAN_POINT('',(-400.,-340.877438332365,87.0411671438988));
#482=CARTESIAN_POINT('',(-400.,-338.689636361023,86.379860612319));
#483=CARTESIAN_POINT('',(-400.,-334.331401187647,85.1255100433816));
#484=CARTESIAN_POINT('',(-400.,-332.161227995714,84.5315634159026));
#485=CARTESIAN_POINT('',(-400.,-327.806162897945,83.4027393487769));
#486=CARTESIAN_POINT('',(-400.,-325.621275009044,82.8678464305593));
#487=CARTESIAN_POINT('',(-400.,-321.238078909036,81.8593151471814));
#488=CARTESIAN_POINT('',(-400.,-319.039774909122,81.38565850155));
#489=CARTESIAN_POINT('',(-400.,-314.631086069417,80.5015804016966));
#490=CARTESIAN_POINT('',(-400.,-312.420704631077,80.0911420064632));
#491=CARTESIAN_POINT('',(-400.,-307.989255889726,79.3352241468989));
#492=CARTESIAN_POINT('',(-400.,-305.768190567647,78.9897330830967));
#493=CARTESIAN_POINT('',(-400.,-301.316866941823,78.3649546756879));
#494=CARTESIAN_POINT('',(-400.,-299.086609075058,78.0856642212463));
#495=CARTESIAN_POINT('',(-400.,-294.599405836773,77.5919853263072));
#496=CARTESIAN_POINT('',(-400.,-292.342396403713,77.3781786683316));
#497=CARTESIAN_POINT('',(-400.,-287.822452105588,77.0190175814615));
#498=CARTESIAN_POINT('',(-400.,-285.559516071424,76.8736778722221));
#499=CARTESIAN_POINT('',(-400.,-281.029912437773,76.6511301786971));
#500=CARTESIAN_POINT('',(-400.,-278.763244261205,76.5739339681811));
#501=CARTESIAN_POINT('',(-400.,-274.228385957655,76.4866428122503));
#502=CARTESIAN_POINT('',(-400.,-271.960195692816,76.4765551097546));
#503=CARTESIAN_POINT('',(-400.,-267.424517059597,76.5217212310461));
#504=CARTESIAN_POINT('',(-400.,-265.15702868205,76.5769741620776));
#505=CARTESIAN_POINT('',(-400.,-260.624992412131,76.7503204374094));
#506=CARTESIAN_POINT('',(-400.,-258.360443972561,76.8683996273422));
#507=CARTESIAN_POINT('',(-400.,-253.825494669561,77.1648868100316));
#508=CARTESIAN_POINT('',(-400.,-251.55511084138,77.3435534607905));
#509=CARTESIAN_POINT('',(-400.,-247.019854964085,77.7572625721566));
#510=CARTESIAN_POINT('',(-400.,-244.754982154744,77.9922967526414));
#511=CARTESIAN_POINT('',(-400.,-240.231229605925,78.5144168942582));
#512=CARTESIAN_POINT('',(-400.,-237.972349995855,78.8015039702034));
#513=CARTESIAN_POINT('',(-400.,-233.460999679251,79.4229369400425));
#514=CARTESIAN_POINT('',(-400.,-231.20852935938,79.7572856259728));
#515=CARTESIAN_POINT('',(-400.,-226.71035263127,80.4680240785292));
#516=CARTESIAN_POINT('',(-400.,-224.464645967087,80.8444122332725));
#517=CARTESIAN_POINT('',(-400.,-219.980301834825,81.6336290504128));
#518=CARTESIAN_POINT('',(-400.,-217.741662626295,82.0464478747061));
#519=CARTESIAN_POINT('',(-400.,-212.540354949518,83.0426932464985));
#520=CARTESIAN_POINT('',(-400.,-209.579933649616,83.6378159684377));
#521=CARTESIAN_POINT('',(-400.,-203.66821087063,84.8681725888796));
#522=CARTESIAN_POINT('',(-400.,-200.716907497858,85.5033974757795));
#523=CARTESIAN_POINT('',(-400.,-194.819612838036,86.7997285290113));
#524=CARTESIAN_POINT('',(-400.,-191.873622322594,87.4608381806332));
#525=CARTESIAN_POINT('',(-400.,-185.98305008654,88.7941764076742));
#526=CARTESIAN_POINT('',(-400.,-183.038469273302,89.4664089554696));
#527=CARTESIAN_POINT('',(-400.,-177.146662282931,90.8066383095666));
#528=CARTESIAN_POINT('',(-400.,-174.199435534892,91.4746326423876));
#529=CARTESIAN_POINT('',(-400.,-169.781671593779,92.4595358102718));
#530=CARTESIAN_POINT('',(-400.,-168.312887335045,92.7842794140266));
#531=CARTESIAN_POINT('',(-400.,-165.373734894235,93.4265140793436));
#532=CARTESIAN_POINT('',(-400.,-163.903366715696,93.7440051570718));
#533=CARTESIAN_POINT('',(-400.,-160.960669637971,94.3695986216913));
#534=CARTESIAN_POINT('',(-400.,-159.488340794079,94.6777012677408));
#535=CARTESIAN_POINT('',(-400.,-157.278053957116,95.1311470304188));
#536=CARTESIAN_POINT('',(-400.,-156.540988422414,95.2808451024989));
#537=CARTESIAN_POINT('',(-400.,-155.066222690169,95.5770862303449));
#538=CARTESIAN_POINT('',(-400.,-154.328522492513,95.7236292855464));
#539=CARTESIAN_POINT('',(-400.,-152.852843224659,96.0129882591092));
#540=CARTESIAN_POINT('',(-400.,-152.114864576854,96.1558063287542));
#541=CARTESIAN_POINT('',(-400.,-150.638092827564,96.4371742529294));
#542=CARTESIAN_POINT('',(-400.,-149.89929972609,96.5757241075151));
#543=CARTESIAN_POINT('',(-400.,-148.420828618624,96.8479569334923));
#544=CARTESIAN_POINT('',(-400.,-147.681150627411,96.9816399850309));
#545=CARTESIAN_POINT('',(-400.,-146.200826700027,97.2435394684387));
#546=CARTESIAN_POINT('',(-400.,-145.460180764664,97.3717559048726));
#547=CARTESIAN_POINT('',(-400.,-143.978326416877,97.622050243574));
#548=CARTESIAN_POINT('',(-400.,-143.237118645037,97.7441319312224));
#549=CARTESIAN_POINT('',(-400.,-141.753640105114,97.9816590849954));
#550=CARTESIAN_POINT('',(-400.,-141.011369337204,98.0971045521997));
#551=CARTESIAN_POINT('',(-400.,-139.525829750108,98.3214577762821));
#552=CARTESIAN_POINT('',(-400.,-138.782560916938,98.4303654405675));
#553=CARTESIAN_POINT('',(-400.,-137.295108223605,98.6417320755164));
#554=CARTESIAN_POINT('',(-400.,-136.55092436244,98.7441910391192));
#555=CARTESIAN_POINT('',(-400.,-134.317343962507,99.041994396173));
#556=CARTESIAN_POINT('',(-400.,-132.826665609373,99.2278033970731));
#557=CARTESIAN_POINT('',(-400.,-129.842459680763,99.5746264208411));
#558=CARTESIAN_POINT('',(-400.,-128.34893214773,99.7356408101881));
#559=CARTESIAN_POINT('',(-400.,-125.605148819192,100.008976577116));
#560=CARTESIAN_POINT('',(-400.,-124.355255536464,100.124951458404));
#561=CARTESIAN_POINT('',(-400.,-121.853782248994,100.340312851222));
#562=CARTESIAN_POINT('',(-400.,-120.602201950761,100.439695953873));
#563=CARTESIAN_POINT('',(-400.,-118.097779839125,100.622124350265));
#564=CARTESIAN_POINT('',(-400.,-116.844937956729,100.705168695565));
#565=CARTESIAN_POINT('',(-400.,-114.337097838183,100.85523379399));
#566=CARTESIAN_POINT('',(-400.,-113.082098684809,100.922239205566));
#567=CARTESIAN_POINT('',(-400.,-110.571447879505,101.040349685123));
#568=CARTESIAN_POINT('',(-400.,-109.315796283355,101.091455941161));
#569=CARTESIAN_POINT('',(-400.,-106.80398901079,101.177986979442));
#570=CARTESIAN_POINT('',(-400.,-105.547833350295,101.213412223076));
#571=CARTESIAN_POINT('',(-400.,-103.350356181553,101.261837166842));
#572=CARTESIAN_POINT('',(-400.,-102.409107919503,101.278233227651));
#573=CARTESIAN_POINT('',(-400.,-100.526501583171,101.302421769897));
#574=CARTESIAN_POINT('',(-400.,-99.5851435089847,101.310214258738));
#575=CARTESIAN_POINT('',(-400.,-97.7025784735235,101.317284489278));
#576=CARTESIAN_POINT('',(-400.,-96.761371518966,101.316563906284));
#577=CARTESIAN_POINT('',(-400.,-94.8789972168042,101.306701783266));
#578=CARTESIAN_POINT('',(-400.,-93.9378298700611,101.297560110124));
#579=CARTESIAN_POINT('',(-400.,-89.2219018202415,101.230881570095));
#580=CARTESIAN_POINT('',(-400.,-85.4477452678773,101.110505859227));
#581=CARTESIAN_POINT('',(-400.,-79.7913080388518,100.834049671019));
#582=CARTESIAN_POINT('',(-400.,-77.9064703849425,100.725902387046));
#583=CARTESIAN_POINT('',(-400.,-74.1388353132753,100.478266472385));
#584=CARTESIAN_POINT('',(-400.,-72.2560378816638,100.33877805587));
#585=CARTESIAN_POINT('',(-400.,-68.4930994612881,100.029259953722));
#586=CARTESIAN_POINT('',(-400.,-66.6129582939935,99.8592324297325));
#587=CARTESIAN_POINT('',(-400.,-62.8555847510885,99.4895260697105));
#588=CARTESIAN_POINT('',(-400.,-60.9783524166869,99.2898468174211));
#589=CARTESIAN_POINT('',(-400.,-55.3522469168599,98.6478807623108));
#590=CARTESIAN_POINT('',(-400.,-51.6081992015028,98.1626018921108));
#591=CARTESIAN_POINT('',(-400.,-44.8773353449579,97.1933835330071));
#592=CARTESIAN_POINT('',(-400.,-41.8877615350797,96.7283068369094));
#593=CARTESIAN_POINT('',(-400.,-35.9189776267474,95.7356170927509));
#594=CARTESIAN_POINT('',(-400.,-32.9397677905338,95.2080024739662));
#595=CARTESIAN_POINT('',(-400.,-24.0159818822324,93.5390966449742));
#596=CARTESIAN_POINT('',(-400.,-18.0873087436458,92.3120473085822));
#597=CARTESIAN_POINT('',(-400.,-9.22324544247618,90.3326462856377));
#598=CARTESIAN_POINT('',(-400.,-6.27202486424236,89.6493601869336));
#599=CARTESIAN_POINT('',(-400.,-0.379317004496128,88.2419497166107));
#600=CARTESIAN_POINT('',(-400.,2.56217033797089,87.5178256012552));
#601=CARTESIAN_POINT('',(-400.,8.43820376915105,86.0334263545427));
#602=CARTESIAN_POINT('',(-400.,11.3727434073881,85.2731257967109));
#603=CARTESIAN_POINT('',(-400.,17.2337230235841,83.7218765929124));
#604=CARTESIAN_POINT('',(-400.,20.1601629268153,82.9309276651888));
#605=CARTESIAN_POINT('',(-400.,28.9291002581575,80.5193777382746));
#606=CARTESIAN_POINT('',(-400.,34.7609655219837,78.8601375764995));
#607=CARTESIAN_POINT('',(-400.,43.5025959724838,76.3198653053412));
#608=CARTESIAN_POINT('',(-400.,46.4195633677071,75.4632919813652));
#609=CARTESIAN_POINT('',(-400.,52.2500151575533,73.7383624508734));
#610=CARTESIAN_POINT('',(-400.,55.1634995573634,72.8700062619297));
#611=CARTESIAN_POINT('',(-400.,60.9863441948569,71.1268462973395));
#612=CARTESIAN_POINT('',(-400.,63.8957058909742,70.2520473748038));
#613=CARTESIAN_POINT('',(-400.,69.7137735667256,68.5002650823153));
#614=CARTESIAN_POINT('',(-400.,72.6224795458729,67.6232817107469));
#615=CARTESIAN_POINT('',(-400.,78.4390456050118,65.8727541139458));
#616=CARTESIAN_POINT('',(-400.,81.3469051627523,64.9992081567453));
#617=CARTESIAN_POINT('',(-400.,87.1651305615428,63.2605051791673));
#618=CARTESIAN_POINT('',(-400.,90.0754963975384,62.395348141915));
#619=CARTESIAN_POINT('',(-400.,95.899155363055,60.6798240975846));
#620=CARTESIAN_POINT('',(-400.,98.8124465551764,59.8294505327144));
#621=CARTESIAN_POINT('',(-400.,104.645163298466,58.1498481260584));
#622=CARTESIAN_POINT('',(-400.,107.564588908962,57.3206194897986));
#623=CARTESIAN_POINT('',(-400.,113.411524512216,55.6911045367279));
#624=CARTESIAN_POINT('',(-400.,116.339034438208,54.8908179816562));
#625=CARTESIAN_POINT('',(-400.,120.737905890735,53.7190781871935));
#626=CARTESIAN_POINT('',(-400.,122.205450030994,53.3332834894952));
#627=CARTESIAN_POINT('',(-400.,125.143361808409,52.5726108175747));
#628=CARTESIAN_POINT('',(-400.,126.613729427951,52.1977327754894));
#629=CARTESIAN_POINT('',(-400.,128.944575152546,51.6139106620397));
#630=CARTESIAN_POINT('',(-400.,129.80403053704,51.4008797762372));
#631=CARTESIAN_POINT('',(-400.,131.524054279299,50.9793636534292));
#632=CARTESIAN_POINT('',(-400.,132.384622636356,50.7708784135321));
#633=CARTESIAN_POINT('',(-400.,134.968339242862,50.152684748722));
#634=CARTESIAN_POINT('',(-400.,136.693249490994,49.750301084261));
#635=CARTESIAN_POINT('',(-400.,140.148381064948,48.9680622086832));
#636=CARTESIAN_POINT('',(-400.,141.878602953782,48.5882094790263));
#637=CARTESIAN_POINT('',(-400.,145.344844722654,47.8545585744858));
#638=CARTESIAN_POINT('',(-400.,147.080865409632,47.50076419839));
#639=CARTESIAN_POINT('',(-400.,150.562951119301,46.8226133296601));
#640=CARTESIAN_POINT('',(-400.,152.309030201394,46.4983286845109));
#641=CARTESIAN_POINT('',(-400.,155.807359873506,45.8850826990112));
#642=CARTESIAN_POINT('',(-400.,157.559610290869,45.5961203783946));
#643=CARTESIAN_POINT('',(-400.,161.070382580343,45.0601884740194));
#644=CARTESIAN_POINT('',(-400.,162.828903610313,44.8132134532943));
#645=CARTESIAN_POINT('',(-400.,165.471476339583,44.4803033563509));
#646=CARTESIAN_POINT('',(-400.,166.353179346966,44.3755875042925));
#647=CARTESIAN_POINT('',(-400.,168.118102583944,44.1798774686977));
#648=CARTESIAN_POINT('',(-400.,169.001322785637,44.0888830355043));
#649=CARTESIAN_POINT('',(-400.,170.694836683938,43.928941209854));
#650=CARTESIAN_POINT('',(-400.,171.505015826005,43.8587831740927));
#651=CARTESIAN_POINT('',(-400.,173.126451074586,43.7321893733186));
#652=CARTESIAN_POINT('',(-400.,173.93770717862,43.675753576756));
#653=CARTESIAN_POINT('',(-400.,175.561051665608,43.5778434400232));
#654=CARTESIAN_POINT('',(-400.,176.373139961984,43.5363676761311));
#655=CARTESIAN_POINT('',(-400.,177.997983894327,43.4697396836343));
#656=CARTESIAN_POINT('',(-400.,178.810739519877,43.4445872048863));
#657=CARTESIAN_POINT('',(-400.,180.436630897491,43.412122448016));
#658=CARTESIAN_POINT('',(-400.,181.249766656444,43.4048105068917));
#659=CARTESIAN_POINT('',(-400.,182.875999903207,43.4097153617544));
#660=CARTESIAN_POINT('',(-400.,183.689097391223,43.4219320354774));
#661=CARTESIAN_POINT('',(-400.,184.904948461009,43.4562055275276));
#662=CARTESIAN_POINT('',(-400.,185.307939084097,43.4701977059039));
#663=CARTESIAN_POINT('',(-400.,186.113689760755,43.5037055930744));
#664=CARTESIAN_POINT('',(-400.,186.51644981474,43.5232212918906));
#665=CARTESIAN_POINT('',(-400.,187.724253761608,43.5903079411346));
#666=CARTESIAN_POINT('',(-400.,188.528842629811,43.6464190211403));
#667=CARTESIAN_POINT('',(-400.,190.136049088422,43.7822653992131));
#668=CARTESIAN_POINT('',(-400.,190.938666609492,43.8620015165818));
#669=CARTESIAN_POINT('',(-400.,192.541121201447,44.0459100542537));
#670=CARTESIAN_POINT('',(-400.,193.340958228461,44.1500828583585));
#671=CARTESIAN_POINT('',(-400.,194.936856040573,44.3835402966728));
#672=CARTESIAN_POINT('',(-400.,195.732917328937,44.5128214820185));
#673=CARTESIAN_POINT('',(-400.,197.320403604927,44.7970505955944));
#674=CARTESIAN_POINT('',(-400.,198.111828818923,44.9519972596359));
#675=CARTESIAN_POINT('',(-400.,199.858063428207,45.3239407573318));
#676=CARTESIAN_POINT('',(-400.,200.81156424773,45.5471196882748));
#677=CARTESIAN_POINT('',(-400.,202.70885596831,46.0322789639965));
#678=CARTESIAN_POINT('',(-400.,203.652644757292,46.2942675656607));
#679=CARTESIAN_POINT('',(-400.,205.528762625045,46.8568898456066));
#680=CARTESIAN_POINT('',(-400.,206.461090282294,47.1575282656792));
#681=CARTESIAN_POINT('',(-400.,208.312682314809,47.7967828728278));
#682=CARTESIAN_POINT('',(-400.,209.231945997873,48.1354010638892));
#683=CARTESIAN_POINT('',(-400.,211.055982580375,48.8494107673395));
#684=CARTESIAN_POINT('',(-400.,211.960756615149,49.2247993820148));
#685=CARTESIAN_POINT('',(-400.,213.764824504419,50.0150901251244));
#686=CARTESIAN_POINT('',(-400.,214.663946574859,50.430383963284));
#687=CARTESIAN_POINT('',(-400.,216.445754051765,51.2947836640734));
#688=CARTESIAN_POINT('',(-400.,217.328439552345,51.743889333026));
#689=CARTESIAN_POINT('',(-400.,219.077062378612,52.6733966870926));
#690=CARTESIAN_POINT('',(-400.,219.943000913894,53.1537961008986));
#691=CARTESIAN_POINT('',(-400.,221.658036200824,54.1429839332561));
#692=CARTESIAN_POINT('',(-400.,222.507139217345,54.6517615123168));
#693=CARTESIAN_POINT('',(-400.,224.188603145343,55.6944535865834));
#694=CARTESIAN_POINT('',(-400.,225.020979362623,56.2283434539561));
#695=CARTESIAN_POINT('',(-400.,226.661274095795,57.3124459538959));
#696=CARTESIAN_POINT('',(-400.,227.469363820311,57.8624001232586));
#697=CARTESIAN_POINT('',(-400.,229.072164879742,58.9815023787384));
#698=CARTESIAN_POINT('',(-400.,229.866875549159,59.5506514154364));
#699=CARTESIAN_POINT('',(-400.,232.232397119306,61.2820642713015));
#700=CARTESIAN_POINT('',(-400.,233.785309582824,62.4687710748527));
#701=CARTESIAN_POINT('',(-400.,236.858919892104,64.886676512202));
#702=CARTESIAN_POINT('',(-400.,238.379573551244,66.117930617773));
#703=CARTESIAN_POINT('',(-400.,241.404960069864,68.6052315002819));
#704=CARTESIAN_POINT('',(-400.,242.909659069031,69.8613191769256));
#705=CARTESIAN_POINT('',(-400.,245.918803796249,72.3791035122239));
#706=CARTESIAN_POINT('',(-400.,247.423244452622,73.6408061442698));
#707=CARTESIAN_POINT('',(-400.,250.446952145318,76.1514801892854));
#708=CARTESIAN_POINT('',(-400.,251.966239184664,77.4004277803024));
#709=CARTESIAN_POINT('',(-400.,254.249041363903,79.2369734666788));
#710=CARTESIAN_POINT('',(-400.,255.0026461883,79.8368639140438));
#711=CARTESIAN_POINT('',(-400.,256.517508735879,81.0268917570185));
#712=CARTESIAN_POINT('',(-400.,257.27876632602,81.6170293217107));
#713=CARTESIAN_POINT('',(-400.,258.810077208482,82.7854769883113));
#714=CARTESIAN_POINT('',(-400.,259.580128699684,83.3637894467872));
#715=CARTESIAN_POINT('',(-400.,261.130270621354,84.506778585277));
#716=CARTESIAN_POINT('',(-400.,261.910360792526,85.0714556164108));
#717=CARTESIAN_POINT('',(-400.,263.480236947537,86.1844094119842));
#718=CARTESIAN_POINT('',(-400.,264.270004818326,86.7327116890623));
#719=CARTESIAN_POINT('',(-400.,265.861231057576,87.8121048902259));
#720=CARTESIAN_POINT('',(-400.,266.662689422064,88.343195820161));
#721=CARTESIAN_POINT('',(-400.,268.276139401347,89.3853838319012));
#722=CARTESIAN_POINT('',(-400.,269.088105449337,89.896520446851));
#723=CARTESIAN_POINT('',(-400.,270.724533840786,90.8984016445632));
#724=CARTESIAN_POINT('',(-400.,271.548996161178,91.3891462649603));
#725=CARTESIAN_POINT('',(-400.,273.209187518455,92.3480289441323));
#726=CARTESIAN_POINT('',(-400.,274.044896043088,92.8162024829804));
#727=CARTESIAN_POINT('',(-400.,275.728814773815,93.7295236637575));
#728=CARTESIAN_POINT('',(-400.,276.577025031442,94.174671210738));
#729=CARTESIAN_POINT('',(-400.,278.285275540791,95.0406319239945));
#730=CARTESIAN_POINT('',(-400.,279.145309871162,95.461456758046));
#731=CARTESIAN_POINT('',(-400.,280.877140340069,96.2780888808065));
#732=CARTESIAN_POINT('',(-400.,281.748936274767,96.6738966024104));
#733=CARTESIAN_POINT('',(-400.,284.048662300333,97.6776011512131));
#734=CARTESIAN_POINT('',(-400.,285.485789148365,98.2645856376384));
#735=CARTESIAN_POINT('',(-400.,288.388110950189,99.369680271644));
#736=CARTESIAN_POINT('',(-400.,289.853336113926,99.8877109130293));
#737=CARTESIAN_POINT('',(-400.,292.807597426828,100.853985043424));
#738=CARTESIAN_POINT('',(-400.,294.296647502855,101.302185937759));
#739=CARTESIAN_POINT('',(-400.,297.293790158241,102.129206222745));
#740=CARTESIAN_POINT('',(-400.,298.801882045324,102.50802812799));
#741=CARTESIAN_POINT('',(-400.,301.870059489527,103.206520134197));
#742=CARTESIAN_POINT('',(-400.,303.430520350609,103.524537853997));
#743=CARTESIAN_POINT('',(-400.,306.563152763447,104.092533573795));
#744=CARTESIAN_POINT('',(-400.,308.135320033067,104.342535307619));
#745=CARTESIAN_POINT('',(-400.,311.288332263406,104.778094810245));
#746=CARTESIAN_POINT('',(-400.,312.869176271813,104.963659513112));
#747=CARTESIAN_POINT('',(-400.,316.036456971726,105.274177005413));
#748=CARTESIAN_POINT('',(-400.,317.622892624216,105.399140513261));
#749=CARTESIAN_POINT('',(-400.,321.125772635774,105.612359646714));
#750=CARTESIAN_POINT('',(-400.,323.04299791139,105.687783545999));
#751=CARTESIAN_POINT('',(-400.,326.879130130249,105.763324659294));
#752=CARTESIAN_POINT('',(-400.,328.798037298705,105.763429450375));
#753=CARTESIAN_POINT('',(-400.,332.635797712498,105.694957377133));
#754=CARTESIAN_POINT('',(-400.,334.554650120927,105.626336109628));
#755=CARTESIAN_POINT('',(-400.,338.390504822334,105.426522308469));
#756=CARTESIAN_POINT('',(-400.,340.30750456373,105.295281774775));
#757=CARTESIAN_POINT('',(-400.,344.137854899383,104.975873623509));
#758=CARTESIAN_POINT('',(-400.,346.051202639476,104.78767214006));
#759=CARTESIAN_POINT('',(-400.,349.783601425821,104.369513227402));
#760=CARTESIAN_POINT('',(-400.,351.602916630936,104.141892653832));
#761=CARTESIAN_POINT('',(-400.,355.23495598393,103.643847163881));
#762=CARTESIAN_POINT('',(-400.,357.047682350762,103.373438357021));
#763=CARTESIAN_POINT('',(-400.,360.664787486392,102.793770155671));
#764=CARTESIAN_POINT('',(-400.,362.469173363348,102.484554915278));
#765=CARTESIAN_POINT('',(-400.,366.067819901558,101.830991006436));
#766=CARTESIAN_POINT('',(-400.,367.862093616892,101.486714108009));
#767=CARTESIAN_POINT('',(-400.,370.545855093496,100.946313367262));
#768=CARTESIAN_POINT('',(-400.,371.437837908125,100.762475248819));
#769=CARTESIAN_POINT('',(-400.,373.220152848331,100.387003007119));
#770=CARTESIAN_POINT('',(-400.,374.110484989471,100.195368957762));
#771=CARTESIAN_POINT('',(-400.,375.,100.));
#772=B_SPLINE_CURVE_WITH_KNOTS('',3,(#470,#471,#472,#473,#474,#475,#476,#477,#478,#479,#480,
#481,#482,#483,#484,#485,#486,#487,#488,#489,#490,#491,#492,#493,#494,#495,#496,#497,#498,#499,
#500,#501,#502,#503,#504,#505,#506,#507,#508,#509,#510,#511,#512,#513,#514,#515,#516,#517,#518,
#519,#520,#521,#522,#523,#524,#525,#526,#527,#528,#529,#530,#531,#532,#533,#534,#535,#536,#537,
#538,#539,#540,#541,#542,#543,#544,#545,#546,#547,#548,#549,#550,#551,#552,#553,#554,#555,#556,
#557,#558,#559,#560,#561,#562,#563,#564,#565,#566,#567,#568,#569,#570,#571,#572,#573,#574,#575,
#576,#577,#578,#579,#580,#581,#582,#583,#584,#585,#586,#587,#588,#589,#590,#591,#592,#593,#594,
#595,#596,#597,#598,#599,#600,#601,#602,#603,#604,#605,#606,#607,#608,#609,#610,#611,#612,#613,
#614,#615,#616,#617,#618,#619,#620,#621,#622,#623,#624,#625,#626,#627,#628,#629,#630,#631,#632,
#633,#634,#635,#636,#637,#638,#639,#640,#641,#642,#643,#644,#645,#646,#647,#648,#649,#650,#651,
#652,#653,#654,#655,#656,#657,#658,#659,#660,#661,#662,#663,#664,#665,#666,#667,#668,#669,#670,
#671,#672,#673,#674,#675,#676,#677,#678,#679,#680,#681,#682,#683,#684,#685,#686,#687,#688,#689,
#690,#691,#692,#693,#694,#695,#696,#697,#698,#699,#700,#701,#702,#703,#704,#705,#706,#707,#708,
#709,#710,#711,#712,#713,#714,#715,#716,#717,#718,#719,#720,#721,#722,#723,#724,#725,#726,#727,
#728,#729,#730,#731,#732,#733,#734,#735,#736,#737,#738,#739,#740,#741,#742,#743,#744,#745,#746,
#747,#748,#749,#750,#751,#752,#753,#754,#755,#756,#757,#758,#759,#760,#761,#762,#763,#764,#765,
#766,#767,#768,#769,#770,#771),.UNSPECIFIED.,.F.,.F.,(4,2,2,2,2,2,2,2,2,2,2,2,2,2,2,2,2,2,2,2,2,
2,2,2,2,2,2,2,2,2,2,2,2,2,2,2,2,2,2,2,2,2,2,2,2,2,2,2,2,2,2,2,2,2,2,2,2,2,2,2,2,2,2,2,2,2,2,2,2,
2,2,2,2,2,2,2,2,2,2,2,2,2,2,2,2,2,2,2,2,2,2,2,2,2,2,2,2,2,2,2,2,2,2,2,2,2,2,2,2,2,2,2,2,2,2,2,2,
2,2,2,2,2,2,2,2,2,2,2,2,2,2,2,2,2,2,2,2,2,2,2,2,2,2,2,2,2,2,2,2,2,4),(0.,6.8343951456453,
13.6780810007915,20.5281168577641,27.3820011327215,34.2376874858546,41.0935968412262,
47.8427510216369,54.5901319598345,61.3354939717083,68.0790452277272,74.8213909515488,
81.5634197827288,88.3637171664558,95.165475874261,101.968409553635,108.772077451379,
115.575652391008,122.377695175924,129.209150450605,136.039602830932,142.870201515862,
149.70120389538,156.53194444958,163.36084597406,172.419372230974,181.475870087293,
190.533591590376,199.594620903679,208.660525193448,213.173278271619,217.686021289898,
222.198639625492,224.454975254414,226.711311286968,228.96631399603,231.221316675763,
233.476282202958,235.731245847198,237.984800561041,240.238354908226,242.491941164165,
244.74552988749,249.251939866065,253.758283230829,257.523960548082,261.290410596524,
265.057079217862,268.827336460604,272.597311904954,276.367176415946,279.191311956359,
282.015445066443,284.839022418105,287.662644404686,298.988009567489,304.651644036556,
310.315239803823,315.978434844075,321.64170939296,332.965953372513,342.041886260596,
351.118047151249,369.276609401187,378.364294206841,387.451921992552,396.546034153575,
405.640229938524,423.829394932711,432.949795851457,442.070183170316,451.18428833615,
460.298400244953,469.407103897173,478.515789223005,487.620325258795,496.724949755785,
505.829499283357,510.381686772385,514.933845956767,517.590225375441,520.246603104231,
525.560130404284,530.874241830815,536.189126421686,541.51662308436,546.84397186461,
552.170630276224,554.834242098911,557.497805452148,559.937334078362,562.37685709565,
564.81614788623,567.25540129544,569.694700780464,572.133984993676,573.343652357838,
574.553317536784,576.972584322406,579.391935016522,581.811323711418,584.230380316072,
586.649317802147,589.586303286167,592.523914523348,595.461886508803,598.400013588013,
601.337909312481,604.308355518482,607.278784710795,610.248998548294,613.218085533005,
616.18431906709,619.116425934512,622.048678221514,627.91061363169,633.780118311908,
639.660263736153,645.550721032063,651.450680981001,654.340269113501,657.229807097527,
660.118763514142,663.007645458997,665.891762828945,668.775879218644,671.653957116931,
674.532029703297,677.405419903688,680.278821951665,683.150833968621,686.022796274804,
690.678041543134,695.338608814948,700.002007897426,704.665237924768,709.441261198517,
714.215615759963,718.989456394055,723.762452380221,729.516895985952,735.272288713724,
741.031402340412,746.794937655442,752.561906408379,758.06185381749,763.559735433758,
769.051417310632,774.53207561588,777.264237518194,779.996373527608),.UNSPECIFIED.);
#773=CARTESIAN_POINT('',(-400.,-375.,100.));
#774=VERTEX_POINT('',#773);
#775=CARTESIAN_POINT('',(-400.,375.,100.));
#776=VERTEX_POINT('',#775);
#777=EDGE_CURVE('E11',#774,#776,#772,.T.);
#778=CARTESIAN_POINT('',(-750.,-375.,100.));
#779=CARTESIAN_POINT('',(-644.685568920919,-375.,100.));
#780=CARTESIAN_POINT('',(-536.684515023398,-375.,100.));
#781=CARTESIAN_POINT('',(-355.235514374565,-375.,100.));
#782=CARTESIAN_POINT('',(-175.903454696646,-375.,100.));
#783=CARTESIAN_POINT('',(47.4554331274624,-375.,100.));
#784=CARTESIAN_POINT('',(285.091607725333,-375.,100.));
#785=CARTESIAN_POINT('',(500.445116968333,-375.,100.));
#786=CARTESIAN_POINT('',(669.085175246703,-375.,100.));
#787=CARTESIAN_POINT('',(750.,-375.,100.));
#788=B_SPLINE_CURVE_WITH_KNOTS('',3,(#778,#779,#780,#781,#782,#783,#784,#785,#786,#787),
.UNSPECIFIED.,.F.,.F.,(4,1,1,1,1,1,1,4),(0.,0.210628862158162,0.216002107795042,
0.362898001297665,0.569292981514,0.66271988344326,0.838170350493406,1.),.UNSPECIFIED.);
#789=EDGE_CURVE('E97',#774,#330,#788,.T.);
#790=CARTESIAN_POINT('',(750.,375.,100.));
#791=CARTESIAN_POINT('',(669.085175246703,375.,100.));
#792=CARTESIAN_POINT('',(500.445116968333,375.,100.));
#793=CARTESIAN_POINT('',(285.091607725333,375.,100.));
#794=CARTESIAN_POINT('',(47.4554331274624,375.,100.));
#795=CARTESIAN_POINT('',(-175.903454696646,375.,100.));
#796=CARTESIAN_POINT('',(-355.235514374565,375.,100.));
#797=CARTESIAN_POINT('',(-536.684515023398,375.,100.));
#798=CARTESIAN_POINT('',(-644.685568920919,375.,100.));
#799=CARTESIAN_POINT('',(-750.,375.,100.));
#800=B_SPLINE_CURVE_WITH_KNOTS('',3,(#790,#791,#792,#793,#794,#795,#796,#797,#798,#799),
.UNSPECIFIED.,.F.,.F.,(4,1,1,1,1,1,1,4),(0.,0.161829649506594,0.33728011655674,0.430707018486,
0.637101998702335,0.783997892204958,0.789371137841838,1.),.UNSPECIFIED.);
#801=EDGE_CURVE('E94',#328,#776,#800,.T.);
#802=ORIENTED_EDGE('',*,*,#777,.F.);
#803=ORIENTED_EDGE('',*,*,#789,.T.);
#804=ORIENTED_EDGE('',*,*,#331,.F.);
#805=ORIENTED_EDGE('',*,*,#801,.T.);
#806=EDGE_LOOP('',(#802,#803,#804,#805));
#807=FACE_BOUND('',#806,.T.);
#808=ADVANCED_FACE('F110',(#807),#469,.F.);
#809=CARTESIAN_POINT('',(-750.,375.,253.111113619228));
#810=DIRECTION('',(0.,-1.,0.));
#811=DIRECTION('',(0.,0.,-1.));
#812=AXIS2_PLACEMENT_3D('',#809,#810,#811);
#813=PLANE('',#812);
#814=DIRECTION('',(0.,0.,-1.));
#815=VECTOR('',#814,1.);
#816=CARTESIAN_POINT('',(-400.,375.,253.120113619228));
#817=LINE('',#816,#815);
#818=EDGE_CURVE('E154',#776,#376,#817,.T.);
#819=ORIENTED_EDGE('',*,*,#818,.F.);
#820=ORIENTED_EDGE('',*,*,#801,.F.);
#821=ORIENTED_EDGE('',*,*,#353,.T.);
#822=ORIENTED_EDGE('',*,*,#383,.T.);
#823=EDGE_LOOP('',(#819,#820,#821,#822));
#824=FACE_BOUND('',#823,.T.);
#825=ADVANCED_FACE('F121',(#824),#813,.F.);
#826=CARTESIAN_POINT('',(-750.,-375.,253.111113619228));
#827=DIRECTION('',(0.,1.,0.));
#828=DIRECTION('',(0.,0.,1.));
#829=AXIS2_PLACEMENT_3D('',#826,#827,#828);
#830=PLANE('',#829);
#831=DIRECTION('',(0.,0.,-1.));
#832=VECTOR('',#831,1.);
#833=CARTESIAN_POINT('',(-400.,-375.,253.120113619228));
#834=LINE('',#833,#832);
#835=EDGE_CURVE('E56',#774,#368,#834,.T.);
#836=ORIENTED_EDGE('',*,*,#835,.T.);
#837=ORIENTED_EDGE('',*,*,#369,.T.);
#838=ORIENTED_EDGE('',*,*,#339,.F.);
#839=ORIENTED_EDGE('',*,*,#789,.F.);
#840=EDGE_LOOP('',(#836,#837,#838,#839));
#841=FACE_BOUND('',#840,.T.);
#842=ADVANCED_FACE('F37',(#841),#830,.F.);
#843=CARTESIAN_POINT('',(-400.,375.,253.120113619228));
#844=DIRECTION('',(-1.,0.,0.));
#845=DIRECTION('',(0.,-1.,0.));
#846=AXIS2_PLACEMENT_3D('',#843,#844,#845);
#847=PLANE('',#846);
#848=ORIENTED_EDGE('',*,*,#777,.T.);
#849=ORIENTED_EDGE('',*,*,#818,.T.);
#850=ORIENTED_EDGE('',*,*,#377,.F.);
#851=ORIENTED_EDGE('',*,*,#835,.F.);
#852=EDGE_LOOP('',(#848,#849,#850,#851));
#853=FACE_BOUND('',#852,.T.);
#854=ADVANCED_FACE('F145',(#853),#847,.T.);
#855=CLOSED_SHELL('',(#357,#388,#808,#825,#842,#854));
#856=MANIFOLD_SOLID_BREP('B2',#855);
#857=ADVANCED_BREP_SHAPE_REPRESENTATION('',(#18,#856),#14);
#858=SHAPE_DEFINITION_REPRESENTATION(#9,#857);
ENDSEC;
END-ISO-10303-21;
